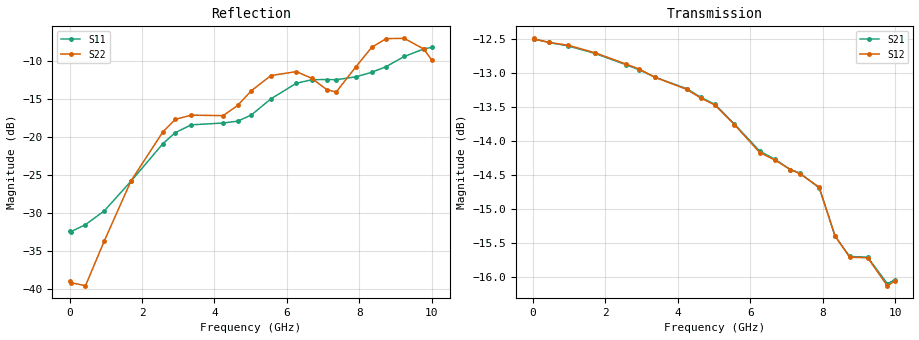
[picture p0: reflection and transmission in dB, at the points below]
! Integrated Device Technology
! Corporate Headquarters
! 6024 Silver Creek Valley Road
! San Jose, CA 95138  USA
! Phone:  1-408-284-8200
! Toll Free:  1-800-223-1366
! Webpage:  http://www.idt.com/
! Timing and RF Division
! 515 Groton Road, Suite 102
! Westford, MA 01886-6024
! Device:  F1958
! Description: 7-bit 0.25 dB Digital Step Attenuator
! Frequency:  0.001 -  6.000 GHz
! Package:  4x4 mm Thin QFN Plastic Package: 24 pin
! Ports:  2 RF, 12 DC
!  Pin  1  = D0
!  Pin  2  = VDD
!  Pin  3  = VMODE
!  Pin  4  = GND
!  Pin  5  = RF1  =  Port 1
!  Pin  6  = GND
!  Pin  7  = GND
!  Pin  8  = GND
!  Pin  9  = GND
!  Pin 10  = GND
!  Pin 11  = GND
!  Pin 12  = GND
!  Pin 13  = GND
!  Pin 14  = RF2  =  Port 2
!  Pin 15  = GND
!  Pin 16  = LE
!  Pin 17  = CLK
!  Pin 18  = DATA
!  Pin 19  = D6
!  Pin 20  = D5
!  Pin 21  = D4
!  Pin 22  = D3
!  Pin 23  = D2
!  Pin 24  = D1
! State:  46
! Atten State:  11.50 dB
! Voltage:  +3.30 Volts
! Current:  0.258 mA
! Data:  The device was measured on a F1958 evaluation board which has
!  individual transmission lines to the RF pins.  Data was collected
!  using a calibrated network analyzer.  The evaluation board was
!  de-embedded using Automatic Fixture Removal (AFR).
!  The reference plane is the edge of the package pin.
! Misc:
!  Action Tracker AT0419
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# GHz S dB R 50
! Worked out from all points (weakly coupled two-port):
!   500 points, 20 MHz to 10 GHz, reference 50 ohm
!   highest |S21| = -12.50 dB at 20 MHz (marker M1); lowest = -16.1 dB at 9.78 GHz (marker M2)
!   lowest |S11| = -32.4 dB at 40 MHz (marker M3), VSWR 1.05, Z = 47.7 - j0.0677 ohm
!   |S11| at or under -10 dB: start of sweep to 9.031 GHz
!   |S22| runs from -39.8 to -6.8 dB; largest |S21 - S12| = 0.0007
!   S11 on the Smith chart (normalised r, x): 20 MHz: 0.95, -0.00; 6.26 GHz: 0.66, +0.16; 10 GHz: 0.66, +0.60
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0.02  -32.41 -178.2  -12.50 -0.5  -12.49 -0.5  -38.93 -9.7
0.04  -32.44 -178.3  -12.50 -0.9  -12.50 -0.9  -39.16 -15.2
0.44  -31.52 175.3  -12.55 -8.4  -12.55 -8.4  -39.55 -62.4
0.96  -29.71 175.0  -12.60 -18.1  -12.59 -18.1  -33.66 -111.5
1.7  -25.79 176.7  -12.71 -31.8  -12.70 -31.8  -25.74 -149.1
2.58  -20.86 -177.3  -12.88 -48.2  -12.87 -48.2  -19.30 -162.6
2.92  -19.42 -174.6  -12.95 -54.5  -12.94 -54.5  -17.68 -165.0
3.36  -18.40 -171.8  -13.06 -62.6  -13.06 -62.7  -17.13 -166.5
4.24  -18.16 -175.8  -13.23 -78.8  -13.24 -78.8  -17.19 166.3
4.64  -17.92 175.5  -13.36 -86.1  -13.37 -86.2  -15.85 148.5
5.02  -17.10 164.3  -13.46 -93.3  -13.47 -93.3  -13.91 136.9
5.56  -14.97 153.2  -13.75 -103.3  -13.76 -103.3  -11.92 133.7
6.26  -12.94 149.3  -14.15 -115.6  -14.17 -115.6  -11.40 137.7
6.68  -12.47 147.3  -14.27 -123.0  -14.28 -122.9  -12.27 134.1
7.1  -12.44 143.1  -14.42 -131.5  -14.42 -131.4  -13.77 117.4
7.36  -12.47 140.5  -14.47 -136.0  -14.48 -135.9  -14.08 96.0
7.9  -12.09 130.0  -14.69 -147.2  -14.68 -147.2  -10.79 71.0
8.34  -11.49 120.4  -15.40 -154.9  -15.40 -155.0  -8.21 66.8
8.74  -10.74 113.4  -15.70 -158.3  -15.71 -158.3  -7.06 70.2
9.24  -9.41 104.7  -15.71 -166.9  -15.72 -167.0  -7.03 79.1
9.78  -8.42 100.1  -16.10 -173.9  -16.13 -173.9  -8.44 81.8
10  -8.21 99.6  -16.04 -176.9  -16.06 -176.8  -9.90 77.9
